VERSION 5.4 ;
NAMESCASESENSITIVE ON ;
BUSBITCHARS "[]" ;
DIVIDERCHAR "/" ;
UNITS
  DATABASE MICRONS 2000 ;
END UNITS
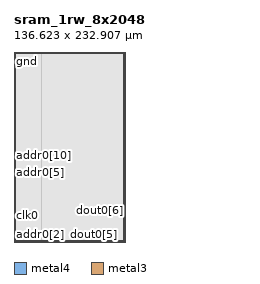
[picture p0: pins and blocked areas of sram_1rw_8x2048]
MACRO sram_1rw_8x2048
   CLASS BLOCK ;
   SIZE 136.6225 BY 232.9075 ;
   SYMMETRY X Y R90 ;
   PIN din0[0]
      DIRECTION INPUT ;
      PORT
         LAYER metal4 ;
         RECT  33.89 0.0 34.03 0.14 ;
      END
   END din0[0]
   PIN din0[1]
      DIRECTION INPUT ;
      PORT
         LAYER metal4 ;
         RECT  36.75 0.0 36.89 0.14 ;
      END
   END din0[1]
   PIN din0[2]
      DIRECTION INPUT ;
      PORT
         LAYER metal4 ;
         RECT  39.61 0.0 39.75 0.14 ;
      END
   END din0[2]
   PIN din0[3]
      DIRECTION INPUT ;
      PORT
         LAYER metal4 ;
         RECT  42.47 0.0 42.61 0.14 ;
      END
   END din0[3]
   PIN din0[4]
      DIRECTION INPUT ;
      PORT
         LAYER metal4 ;
         RECT  45.33 0.0 45.47 0.14 ;
      END
   END din0[4]
   PIN din0[5]
      DIRECTION INPUT ;
      PORT
         LAYER metal4 ;
         RECT  48.19 0.0 48.33 0.14 ;
      END
   END din0[5]
   PIN din0[6]
      DIRECTION INPUT ;
      PORT
         LAYER metal4 ;
         RECT  51.05 0.0 51.19 0.14 ;
      END
   END din0[6]
   PIN din0[7]
      DIRECTION INPUT ;
      PORT
         LAYER metal4 ;
         RECT  53.91 0.0 54.05 0.14 ;
      END
   END din0[7]
   PIN addr0[0]
      DIRECTION INPUT ;
      PORT
         LAYER metal4 ;
         RECT  22.45 0.0 22.59 0.14 ;
      END
   END addr0[0]
   PIN addr0[1]
      DIRECTION INPUT ;
      PORT
         LAYER metal4 ;
         RECT  25.31 0.0 25.45 0.14 ;
      END
   END addr0[1]
   PIN addr0[2]
      DIRECTION INPUT ;
      PORT
         LAYER metal4 ;
         RECT  28.17 0.0 28.31 0.14 ;
      END
   END addr0[2]
   PIN addr0[3]
      DIRECTION INPUT ;
      PORT
         LAYER metal4 ;
         RECT  31.03 0.0 31.17 0.14 ;
      END
   END addr0[3]
   PIN addr0[4]
      DIRECTION INPUT ;
      PORT
         LAYER metal3 ;
         RECT  0.0 81.95 0.14 82.09 ;
      END
   END addr0[4]
   PIN addr0[5]
      DIRECTION INPUT ;
      PORT
         LAYER metal3 ;
         RECT  0.0 84.68 0.14 84.82 ;
      END
   END addr0[5]
   PIN addr0[6]
      DIRECTION INPUT ;
      PORT
         LAYER metal3 ;
         RECT  0.0 86.89 0.14 87.03 ;
      END
   END addr0[6]
   PIN addr0[7]
      DIRECTION INPUT ;
      PORT
         LAYER metal3 ;
         RECT  0.0 89.62 0.14 89.76 ;
      END
   END addr0[7]
   PIN addr0[8]
      DIRECTION INPUT ;
      PORT
         LAYER metal3 ;
         RECT  0.0 91.83 0.14 91.97 ;
      END
   END addr0[8]
   PIN addr0[9]
      DIRECTION INPUT ;
      PORT
         LAYER metal3 ;
         RECT  0.0 94.56 0.14 94.7 ;
      END
   END addr0[9]
   PIN addr0[10]
      DIRECTION INPUT ;
      PORT
         LAYER metal3 ;
         RECT  0.0 96.77 0.14 96.91 ;
      END
   END addr0[10]
   PIN csb0
      DIRECTION INPUT ;
      PORT
         LAYER metal3 ;
         RECT  0.0 31.77 0.14 31.91 ;
      END
   END csb0
   PIN web0
      DIRECTION INPUT ;
      PORT
         LAYER metal3 ;
         RECT  0.0 34.5 0.14 34.64 ;
      END
   END web0
   PIN clk0
      DIRECTION INPUT ;
      PORT
         LAYER metal3 ;
         RECT  0.0 32.005 0.14 32.145 ;
      END
   END clk0
   PIN dout0[0]
      DIRECTION OUTPUT ;
      PORT
         LAYER metal4 ;
         RECT  41.425 0.0 41.565 0.14 ;
      END
   END dout0[0]
   PIN dout0[1]
      DIRECTION OUTPUT ;
      PORT
         LAYER metal4 ;
         RECT  52.705 0.0 52.845 0.14 ;
      END
   END dout0[1]
   PIN dout0[2]
      DIRECTION OUTPUT ;
      PORT
         LAYER metal4 ;
         RECT  63.985 0.0 64.125 0.14 ;
      END
   END dout0[2]
   PIN dout0[3]
      DIRECTION OUTPUT ;
      PORT
         LAYER metal4 ;
         RECT  75.265 0.0 75.405 0.14 ;
      END
   END dout0[3]
   PIN dout0[4]
      DIRECTION OUTPUT ;
      PORT
         LAYER metal4 ;
         RECT  86.545 0.0 86.685 0.14 ;
      END
   END dout0[4]
   PIN dout0[5]
      DIRECTION OUTPUT ;
      PORT
         LAYER metal4 ;
         RECT  97.825 0.0 97.965 0.14 ;
      END
   END dout0[5]
   PIN dout0[6]
      DIRECTION OUTPUT ;
      PORT
         LAYER metal3 ;
         RECT  136.4825 38.3725 136.6225 38.5125 ;
      END
   END dout0[6]
   PIN dout0[7]
      DIRECTION OUTPUT ;
      PORT
         LAYER metal3 ;
         RECT  136.4825 38.1375 136.6225 38.2775 ;
      END
   END dout0[7]
   PIN vdd
      DIRECTION INOUT ;
      USE POWER ; 
      SHAPE ABUTMENT ; 
      PORT
         LAYER metal3 ;
         RECT  0.0 232.2075 136.6225 232.9075 ;
         LAYER metal4 ;
         RECT  135.9225 0.0 136.6225 232.9075 ;
         LAYER metal4 ;
         RECT  0.0 0.0 0.7 232.9075 ;
         LAYER metal3 ;
         RECT  0.0 0.0 136.6225 0.7 ;
      END
   END vdd
   PIN gnd
      DIRECTION INOUT ;
      USE GROUND ; 
      SHAPE ABUTMENT ; 
      PORT
         LAYER metal3 ;
         RECT  1.4 1.4 135.2225 2.1 ;
         LAYER metal4 ;
         RECT  1.4 1.4 2.1 231.5075 ;
         LAYER metal4 ;
         RECT  134.5225 1.4 135.2225 231.5075 ;
         LAYER metal3 ;
         RECT  1.4 230.8075 135.2225 231.5075 ;
      END
   END gnd
   OBS
   LAYER  metal1 ;
      RECT  0.14 0.14 136.4825 232.7675 ;
   LAYER  metal2 ;
      RECT  0.14 0.14 136.4825 232.7675 ;
   LAYER  metal3 ;
      RECT  0.28 81.81 136.4825 82.23 ;
      RECT  0.14 82.23 0.28 84.54 ;
      RECT  0.14 84.96 0.28 86.75 ;
      RECT  0.14 87.17 0.28 89.48 ;
      RECT  0.14 89.9 0.28 91.69 ;
      RECT  0.14 92.11 0.28 94.42 ;
      RECT  0.14 94.84 0.28 96.63 ;
      RECT  0.14 34.78 0.28 81.81 ;
      RECT  0.14 32.285 0.28 34.36 ;
      RECT  0.28 38.2325 136.3425 38.6525 ;
      RECT  0.28 38.6525 136.3425 81.81 ;
      RECT  136.3425 38.6525 136.4825 81.81 ;
      RECT  0.14 97.05 0.28 232.0675 ;
      RECT  0.14 0.84 0.28 31.63 ;
      RECT  136.3425 0.84 136.4825 37.9975 ;
      RECT  0.28 0.84 1.26 1.26 ;
      RECT  0.28 1.26 1.26 2.24 ;
      RECT  0.28 2.24 1.26 38.2325 ;
      RECT  1.26 0.84 135.3625 1.26 ;
      RECT  1.26 2.24 135.3625 38.2325 ;
      RECT  135.3625 0.84 136.3425 1.26 ;
      RECT  135.3625 1.26 136.3425 2.24 ;
      RECT  135.3625 2.24 136.3425 38.2325 ;
      RECT  0.28 82.23 1.26 230.6675 ;
      RECT  0.28 230.6675 1.26 231.6475 ;
      RECT  0.28 231.6475 1.26 232.0675 ;
      RECT  1.26 82.23 135.3625 230.6675 ;
      RECT  1.26 231.6475 135.3625 232.0675 ;
      RECT  135.3625 82.23 136.4825 230.6675 ;
      RECT  135.3625 230.6675 136.4825 231.6475 ;
      RECT  135.3625 231.6475 136.4825 232.0675 ;
   LAYER  metal4 ;
      RECT  33.61 0.42 34.31 232.7675 ;
      RECT  34.31 0.14 36.47 0.42 ;
      RECT  37.17 0.14 39.33 0.42 ;
      RECT  42.89 0.14 45.05 0.42 ;
      RECT  45.75 0.14 47.91 0.42 ;
      RECT  48.61 0.14 50.77 0.42 ;
      RECT  22.87 0.14 25.03 0.42 ;
      RECT  25.73 0.14 27.89 0.42 ;
      RECT  28.59 0.14 30.75 0.42 ;
      RECT  31.45 0.14 33.61 0.42 ;
      RECT  40.03 0.14 41.145 0.42 ;
      RECT  41.845 0.14 42.19 0.42 ;
      RECT  51.47 0.14 52.425 0.42 ;
      RECT  53.125 0.14 53.63 0.42 ;
      RECT  54.33 0.14 63.705 0.42 ;
      RECT  64.405 0.14 74.985 0.42 ;
      RECT  75.685 0.14 86.265 0.42 ;
      RECT  86.965 0.14 97.545 0.42 ;
      RECT  98.245 0.14 135.6425 0.42 ;
      RECT  0.98 0.14 22.17 0.42 ;
      RECT  0.98 0.42 1.12 1.12 ;
      RECT  0.98 1.12 1.12 231.7875 ;
      RECT  0.98 231.7875 1.12 232.7675 ;
      RECT  1.12 0.42 2.38 1.12 ;
      RECT  1.12 231.7875 2.38 232.7675 ;
      RECT  2.38 0.42 33.61 1.12 ;
      RECT  2.38 1.12 33.61 231.7875 ;
      RECT  2.38 231.7875 33.61 232.7675 ;
      RECT  34.31 0.42 134.2425 1.12 ;
      RECT  34.31 1.12 134.2425 231.7875 ;
      RECT  34.31 231.7875 134.2425 232.7675 ;
      RECT  134.2425 0.42 135.5025 1.12 ;
      RECT  134.2425 231.7875 135.5025 232.7675 ;
      RECT  135.5025 0.42 135.6425 1.12 ;
      RECT  135.5025 1.12 135.6425 231.7875 ;
      RECT  135.5025 231.7875 135.6425 232.7675 ;
   END
END    sram_1rw_8x2048
END    LIBRARY
